VERSION 5.7 ;
  NOWIREEXTENSIONATPIN ON ;
  DIVIDERCHAR "/" ;
  BUSBITCHARS "[]" ;
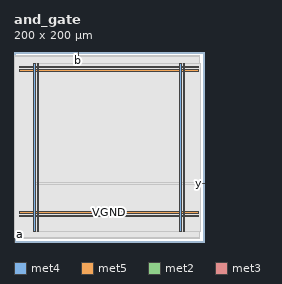
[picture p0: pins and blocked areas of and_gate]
MACRO and_gate
  CLASS BLOCK ;
  FOREIGN and_gate ;
  ORIGIN 0.000 0.000 ;
  SIZE 200.000 BY 200.000 ;
  PIN VGND
    DIRECTION INOUT ;
    USE GROUND ;
    PORT
      LAYER met4 ;
        RECT 24.340 10.640 25.940 187.920 ;
    END
    PORT
      LAYER met4 ;
        RECT 177.940 10.640 179.540 187.920 ;
    END
    PORT
      LAYER met5 ;
        RECT 5.280 30.030 194.360 31.630 ;
    END
    PORT
      LAYER met5 ;
        RECT 5.280 183.210 194.360 184.810 ;
    END
  END VGND
  PIN VPWR
    DIRECTION INOUT ;
    USE POWER ;
    PORT
      LAYER met4 ;
        RECT 21.040 10.640 22.640 187.920 ;
    END
    PORT
      LAYER met4 ;
        RECT 174.640 10.640 176.240 187.920 ;
    END
    PORT
      LAYER met5 ;
        RECT 5.280 26.730 194.360 28.330 ;
    END
    PORT
      LAYER met5 ;
        RECT 5.280 179.910 194.360 181.510 ;
    END
  END VPWR
  PIN a
    DIRECTION INPUT ;
    USE SIGNAL ;
    ANTENNAGATEAREA 0.196500 ;
    PORT
      LAYER met2 ;
        RECT 0.090 0.000 0.370 4.000 ;
    END
  END a
  PIN b
    DIRECTION INPUT ;
    USE SIGNAL ;
    ANTENNAGATEAREA 0.196500 ;
    PORT
      LAYER met2 ;
        RECT 67.710 196.000 67.990 200.000 ;
    END
  END b
  PIN y
    DIRECTION OUTPUT TRISTATE ;
    USE SIGNAL ;
    ANTENNADIFFAREA 0.795200 ;
    PORT
      LAYER met3 ;
        RECT 196.000 61.240 200.000 61.840 ;
    END
  END y
  OBS
      LAYER li1 ;
        RECT 5.520 10.795 194.120 187.765 ;
      LAYER met1 ;
        RECT 0.070 10.640 194.970 187.920 ;
      LAYER met2 ;
        RECT 0.100 195.720 67.430 196.000 ;
        RECT 68.270 195.720 194.950 196.000 ;
        RECT 0.100 4.280 194.950 195.720 ;
        RECT 0.650 4.000 194.950 4.280 ;
      LAYER met3 ;
        RECT 21.050 62.240 196.000 187.845 ;
        RECT 21.050 60.840 195.600 62.240 ;
        RECT 21.050 10.715 196.000 60.840 ;
  END
END and_gate
END LIBRARY

